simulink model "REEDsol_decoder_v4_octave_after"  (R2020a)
settings: Solver=VariableStepAuto  StartTime=0.0  StopTime=700  RelTol=1e-3
InitFcn:
  | FrameSize = 32+1784+256+32;
  | SamplingTime = 1/(38.4e3)*2;
  | IQframeSize = (32+1784+256+32)/2;
  | %同期コードが必ず含まれるように32を足す
  | h_time = 1;
  | 
  | % General simulation parameters
  | M = 4;                         % M-PSK alphabet size
  | Upsampling = 4;            % Upsampling factor
  | Downsampling = 2;        % Downsampling factor
  | Fs = 2e6;                     % Sample rate
  | Ts = 1/Fs;                    % Sample time
  | %%FrameSize = 111;          % Number of modulated symbols per frame
  | %MessageLength = 105;  % Number of message bits per frame, 7 ASCII characters
  | BarkerLength = 13;        % Number of Barker code symbols
  | 
  | % TED
  | %fs = 2.4e6;
  | %fs = Fs/2;
  | fs = Fs;
  | Rdata = 100e3;
  | Rsymbol = Rdata/2;
  | 
  | % --- Early Late Timing Synchronisation ----
  | % synch loop design
  | d = 0.707;                   % damping ratio
  | 
  | %Ts = 1/Rsymbol;           % symbol period
  | Ks = 3.22;                    % phase detector coefficient
  | BnS = 0.1*Rsymbol;      % noise bandwidth in Hz
  | Kn   = 1;                      % gain of numerically controlled clock
  | 
  | % calculate loop filter coefficients
  | Ka = (4*d*BnS*Ts)/(Kn*Ks*(d+1/(4*d)));
  | Kb = (4*(BnS*Ts)^2)/(Kn*Ks*(d+1/4*d)^2);
undefined symbols (not defined in the file or in its folder): Column, D, vector
libraries: commutil2 x2

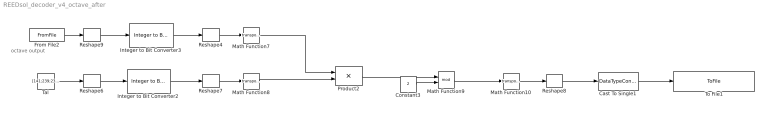
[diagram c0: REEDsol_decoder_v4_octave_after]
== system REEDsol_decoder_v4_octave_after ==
  note: octave output
  Cast To Single1 : DataTypeConversion  OutDataTypeStr=double
  Constant3 : Constant  Value=2  VectorParams1D=off  OutDataTypeStr=single
  From File2 : FromFile  FileName=C:\Users\Eve\Desktop\sample_code_Simulink\data_analysis\octave_output.mat  SampleTime=0.05395833  ExtrapolationBeforeFirstDataPoint=Ground value  InterpolationWithinTimeRange=Zero order hold  ExtrapolationAfterLastDataPoint=Ground value
  Integer to Bit Converter2 : commutil2/Integer to Bit Converter  nbits=8  signedInputValues=Unsigned  bitOrder=MSB first  outDtype=single
  Integer to Bit Converter3 : commutil2/Integer to Bit Converter  nbits=8  signedInputValues=Unsigned  bitOrder=MSB first  outDtype=single
  Math Function10 : Math  Operator=transpose  SignedPower=on
  Math Function7 : Math  Operator=transpose  SignedPower=on  OutputSignalType=real
  Math Function8 : Math  Operator=transpose  SignedPower=on
  Math Function9 : Math  Operator=mod  SignedPower=on
  Product2 : Product  Multiplication=Matrix(*)
  Reshape4 : Reshape  OutputDimensionality=Customize  OutputDimensions=[8,223]
  Reshape6 : Reshape  OutputDimensionality=Column vector (2-D)  OutputDimensions=[1,8]
  Reshape7 : Reshape  OutputDimensionality=Customize  OutputDimensions=[8,8]
  Reshape8 : Reshape  OutputDimensionality=Column vector (2-D)  OutputDimensions=[1,8]
  Reshape9 : Reshape  OutputDimensionality=Column vector (2-D)
  Tal : Constant  Value=[141;239;236;134;250;153;175;123]  VectorParams1D=off  OutDataTypeStr=single
  To File1 : ToFile  Filename=C:\Users\Eve\Desktop\sample_code_Simulink\data_analysis\RS_decodedata.mat
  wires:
  Reshape4/1 -> Math Function7/1
  Math Function7/1 -> Product2/1
  Integer to Bit Converter2/1 -> Reshape7/1
  Reshape6/1 -> Integer to Bit Converter2/1
  Reshape7/1 -> Math Function8/1
  Math Function8/1 -> Product2/2
  Product2/1 -> Math Function9/1
  Constant3/1 -> Math Function9/2
  Math Function9/1 -> Math Function10/1
  Math Function10/1 -> Reshape8/1
  Reshape8/1 -> Cast To Single1/1
  Tal/1 -> Reshape6/1
  Cast To Single1/1 -> To File1/1
  From File2/1 -> Reshape9/1
  Reshape9/1 -> Integer to Bit Converter3/1
  Integer to Bit Converter3/1 -> Reshape4/1
